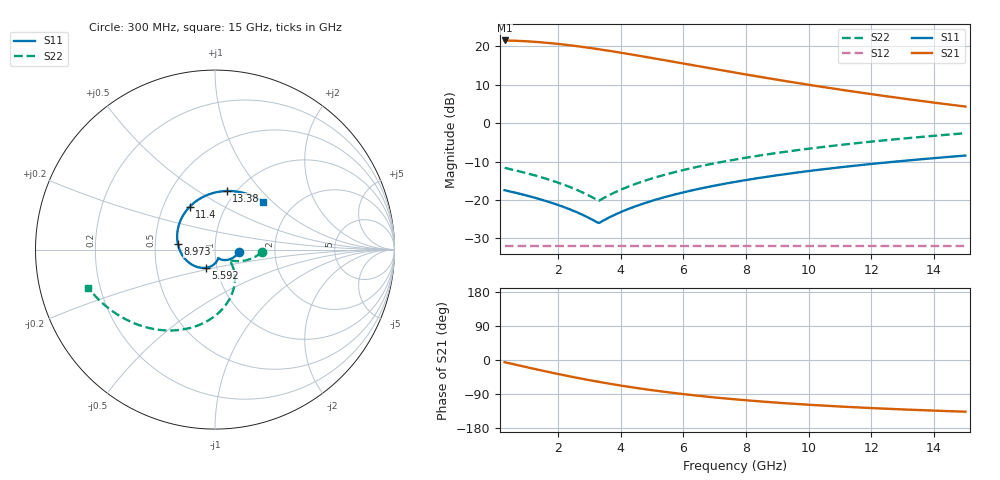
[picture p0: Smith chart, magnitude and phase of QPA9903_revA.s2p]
! written by passband
# GHZ S MA R 50
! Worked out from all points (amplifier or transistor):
!   201 points, 300 MHz to 15 GHz, reference 50 ohm
!   highest |S21| = 21.5 dB at 300 MHz (marker M1)
!   |S21| within 3 dB of that: start of sweep to 3.87 GHz
!   unconditionally stable (mu >= 1): start of sweep to end of sweep
!   at 2.725 GHz: K = 2.10, MAG = 20.0 dB, |S12| = -32.0 dB
!   at 7.65 GHz: K = 3.89, MAG = 13.7 dB, |S12| = -32.0 dB
!   at 15 GHz: K = 4.98, MAG = 8.2 dB, |S12| = -32.0 dB
!   S11 on the Smith chart (normalised r, x): 300 MHz: 1.31, -0.04; 5.592 GHz: 0.88, -0.18; 8.973 GHz: 0.66, +0.04; 11.4 GHz: 0.68, +0.35; 13.38 GHz: 0.91, +0.67; 15 GHz: 1.41, +0.88
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0.3  0.1341 -6.3  11.86 -5.7  0.02512 -11.1  0.2618 -3.3
0.594  0.1258 -12.5  11.77 -11.3  0.02512 -22.0  0.2456 -6.5
0.888  0.1176 -18.7  11.63 -16.8  0.02512 -32.9  0.2295 -9.7
1.2555  0.1073 -26.4  11.39 -23.6  0.02512 -46.5  0.2094 -13.7
1.623  0.09696 -34.1  11.07 -30.3  0.02512 -60.1  0.1893 -17.7
1.917  0.0887 -40.3  10.78 -35.4  0.02512 -71.0  0.1732 -20.9
2.211  0.08045 -46.5  10.46 -40.5  0.02512 -81.9  0.157 -24.1
2.505  0.0722 -52.6  10.12 -45.3  0.02512 -92.8  0.1409 -27.3
2.799  0.06394 -58.8  9.761 -50.0  0.02512 -103.7  0.1248 -30.5
3.3135  0.05026 -69.6  9.107 -57.8  0.02512 -122.7  0.09811 -36.1
3.828  0.0647 -80.4  8.447 -65.1  0.02512 -141.8  0.1263 -41.7
4.4895  0.08327 -94.3  7.619 -73.6  0.02512 -166.3  0.1625 -48.9
5.2245  0.1039 -109.8  6.76 -82.1  0.02512 166.5  0.2028 -56.9
5.592  0.1142 -117.5  6.36 -86.0  0.02512 152.9  0.223 -60.9
6.5475  0.141 -137.6  5.425 -95.0  0.02512 117.5  0.2753 -71.3
7.65  0.172 -160.7  4.527 -103.8  0.02512 76.7  0.3357 -83.3
8.973  0.2091 171.5  3.672 -112.5  0.02512 27.7  0.4082 -97.7
10.149  0.2421 146.8  3.078 -118.8  0.02512 -15.9  0.4727 -110.5
11.3985  0.2772 120.5  2.579 -124.5  0.02512 -62.1  0.5411 -124.1
12.5745  0.3102 95.8  2.204 -129.0  0.02512 -105.7  0.6056 -136.9
13.383  0.3329 78.8  1.989 -131.7  0.02512 -135.6  0.6499 -145.7
15  0.3783 44.8  1.639 -136.4  0.02512 164.5  0.7385 -163.3
